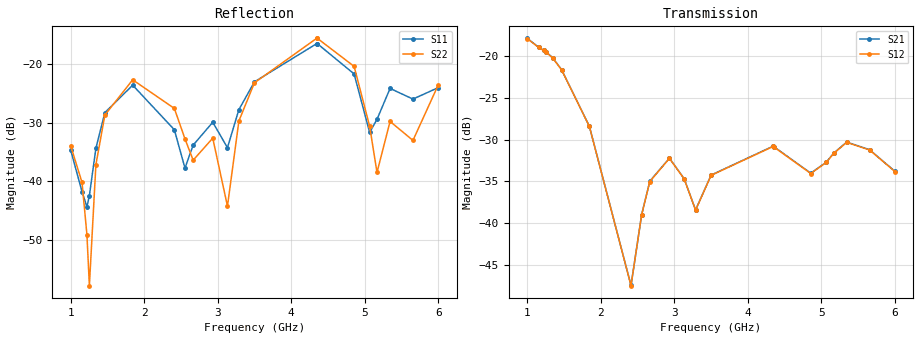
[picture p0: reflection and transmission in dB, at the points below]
!Agilent Technologies,E8364B,MY43040528,A.07.50.67
!Agilent E8364B: A.07.50.67
!Date: Sunday, March 01, 2026 22:17:55
!Correction: S11(Full 2 Port(1,2))
!S21(Full 2 Port(1,2))
!S12(Full 2 Port(1,2))
!S22(Full 2 Port(1,2))
!S2P File: Measurements: S11, S21, S12, S22:
# Hz S  dB  R 50
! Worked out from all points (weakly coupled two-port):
!   451 points, 1 GHz to 6 GHz, reference 50 ohm
!   highest |S21| = -17.89 dB at 1 GHz (marker M1); lowest = -47.5 dB at 2.411 GHz (marker M2)
!   lowest |S11| = -44.3 dB at 1.222 GHz (marker M3), VSWR 1.01, Z = 50.3 - j0.537 ohm
!   |S11| at or under -10 dB: start of sweep to end of sweep
!   |S22| runs from -57.8 to -15.6 dB; largest |S21 - S12| = 0.00048
!   S11 on the Smith chart (normalised r, x): 1 GHz: 1.04, +0.01; 4.356 GHz: 1.20, -0.26; 6 GHz: 0.96, -0.12
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1e9  -34.58 12.7  -17.89 28.9  -17.92 28.9  -33.87 -29.8
1.155556e9  -41.73 -14.8  -18.95 -17.4  -18.98 -17.4  -40.16 -32.0
1.222222e9  -44.33 -61.5  -19.31 -38.3  -19.34 -38.3  -49.06 -48.9
1.255556e9  -42.41 -98.5  -19.51 -49.1  -19.54 -49.1  -57.78 -143.3
1.344444e9  -34.33 -149.3  -20.20 -78.8  -20.23 -78.7  -37.12 121.5
1.466667e9  -28.25 168.8  -21.63 -119.8  -21.66 -119.8  -28.66 84.7
1.844444e9  -23.57 83.0  -28.40 122.0  -28.43 122.1  -22.66 -14.0
2.411111e9  -31.18 7.6  -47.46 -126.5  -47.50 -126.5  -27.54 -124.1
2.555556e9  -37.72 32.2  -38.99 114.5  -39.02 114.5  -32.73 -141.4
2.666667e9  -33.80 67.1  -34.99 63.9  -35.03 64.0  -36.37 -119.4
2.933333e9  -29.90 37.2  -32.23 -42.1  -32.26 -42.1  -32.61 -135.2
3.133333e9  -34.24 56.3  -34.68 -110.3  -34.71 -110.3  -44.22 -109.6
3.288889e9  -27.74 76.2  -38.42 -135.3  -38.46 -135.2  -29.67 -74.9
3.5e9  -23.01 49.4  -34.26 -154.1  -34.29 -154.1  -23.17 -119.5
4.344444e9  -16.51 -44.2  -30.79 -89.8  -30.83 -89.8  -15.60 104.0
4.355556e9  -16.50 -45.9  -30.87 -93.8  -30.91 -93.8  -15.59 101.8
4.855556e9  -21.66 -128.0  -34.03 45.4  -34.07 45.4  -20.37 -7.6
5.066667e9  -31.63 -118.5  -32.71 -72.0  -32.74 -72.0  -30.58 -46.2
5.166667e9  -29.40 -77.4  -31.63 -123.2  -31.67 -123.2  -38.46 1.0
5.344444e9  -24.13 -88.5  -30.31 154.1  -30.34 154.1  -29.76 20.3
5.655556e9  -25.95 -116.6  -31.22 28.5  -31.26 28.5  -33.00 10.6
6e9  -23.99 -104.5  -33.81 -68.9  -33.84 -68.9  -23.52 -3.7
